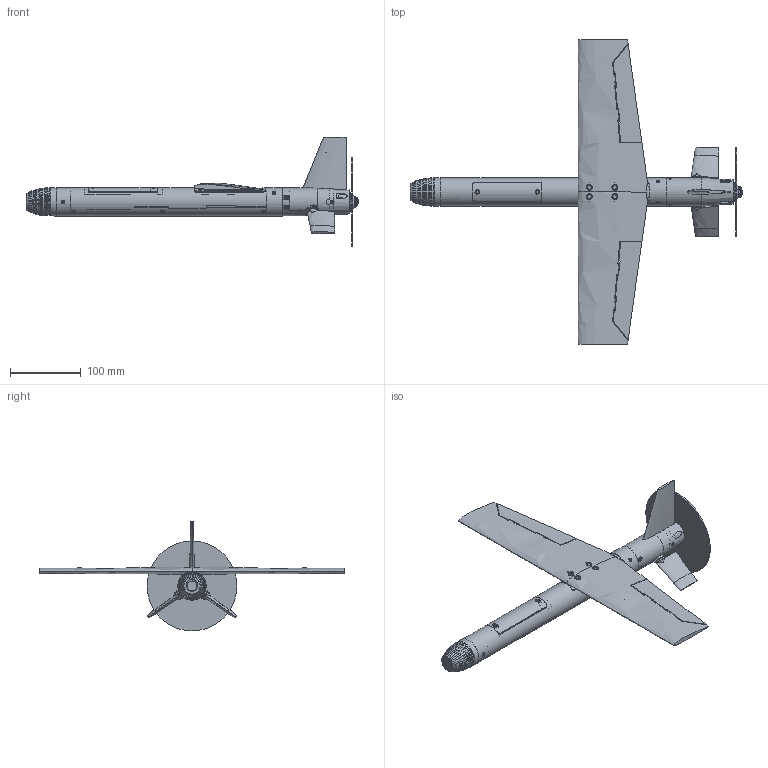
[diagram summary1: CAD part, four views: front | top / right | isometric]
STEP (ISO 10303-21) file: header records copied from the file, then geometry measured from it (millimetres).
FILE_DESCRIPTION(('SkyG Speed 90B - revision C6B-18 - 2026-10-15','C6B-assembly'),'2;1');
FILE_NAME('C6B-assembly_C6B-18','2026-10-15T11:37:26',('Author'),( 'Open CASCADE'),'Open CASCADE STEP processor 7.9','Open CASCADE 7.9' ,'Unknown');
FILE_SCHEMA(('AUTOMOTIVE_DESIGN { 1 0 10303 214 1 1 1 1 }'));
Length unit declared in the file: millimetre
Products named in the file (172): C4; N0M-nose-micro-camera; N0M-vtx-shelf; F3-tail-module; WR-wing-right; WL-wing-left; AR-aileron-right; AL-aileron-left; SR-stabilator-right; SL-stabilator-left; FN-fin; AHR-aileron-horn-right; AHL-aileron-horn-left; THR-tail-horn-right; THL-tail-horn-left; TR-equipment-tray; BF-battery-front-stop; TC-tail-coupler; CW-countersunk-washer; NB1-wing-nut-bar-front; NB2-wing-nut-bar-rear; HL1-hatch-lip-front; HL2-hatch-lip-rear; HF-front-hatch; WF-wing-window-filler; HG-gps-carrier; M1-motor-plate; SP-spinner; ENV-scr_mplate_R; ENV-cw_15; ENV-scr_mplate_L; ENV-cw_16; ENV-motor; ENV-prop_disc; ENV-prop_hub_nut; ENV-battery; ENV-camera_micro19; ENV-cam_screws; ENV-O_o4_camera; ENV-O_window ...
Assembly tree (171 placements, depth 2):
  C4
    N0M-nose-micro-camera
    N0M-vtx-shelf
    F3-tail-module
    WR-wing-right
    WL-wing-left
    AR-aileron-right
    AL-aileron-left
    SR-stabilator-right
    SL-stabilator-left
    FN-fin
    AHR-aileron-horn-right
    AHL-aileron-horn-left
    THR-tail-horn-right
    THL-tail-horn-left
    TR-equipment-tray
    BF-battery-front-stop
    TC-tail-coupler
    CW-countersunk-washer
    NB1-wing-nut-bar-front
    NB2-wing-nut-bar-rear
    HL1-hatch-lip-front
    HL2-hatch-lip-rear
    HF-front-hatch
    WF-wing-window-filler
    HG-gps-carrier
    M1-motor-plate
    SP-spinner
    ENV-scr_mplate_R
    ENV-cw_15
    ENV-scr_mplate_L
    ENV-cw_16
    ENV-motor
    ENV-prop_disc
    ENV-prop_hub_nut
    ENV-battery
    ENV-camera_micro19
    ENV-cam_screws
    ENV-O_o4_camera
    ENV-O_window
    ENV-O_o4_screws
    ENV-O_o4_module
    ENV-vtx
    ENV-gnss
    ENV-flight_controller
    ENV-ail_servo_arm
    ENV-ail_rod_R
    ENV-ail_link_R
    ENV-ail_rod_L
    ENV-ail_link_L
    ENV-ail_spine_R
    ENV-ail_spine_L
    ENV-receiver
    ENV-ant_elrs
    ENV-ant_vtx
    ENV-O_ant_video
    ENV-aileron_servo
    ENV-tail_servo_L
    ENV-tail_servo_R
    ENV-esc
Bounding box: 469.18 x 430 x 155.1 mm (x, y, z)
Volume: 496095.7 mm3; surface area: 354199.1 mm2
Topology: 221 solids, 223 shells, 2850 faces, 7158 edges, 4748 vertices
Faces by surface type: plane 1799, cylinder 612, bspline 237, cone 155, sphere 21, torus 15, revolution 11
Full cylindrical faces by diameter (mm): 0.98 x6, 1.107 x11, 1.2 x22, 1.25 x8, 1.5 x2, 1.6 x20, 1.65 x2, 1.75 x4, 1.9 x1, 2 x34, 2.1 x4, 2.2 x22, 2.5 x2, 2.6 x4, 2.842 x6, 3 x19, 3.05 x2, 3.2 x8, 3.3 x6, 3.8 x2, 3.9 x3, 3.94 x3, 4 x4, 4.9 x16, 5 x14, 5.2 x3, 5.5 x4, 5.6 x3, 6 x5, 6.3 x2
Entity records: 482649 total; most frequent: CARTESIAN_POINT 344876, DIRECTION 21708, ORIENTED_EDGE 14274, PCURVE 14274, DEFINITIONAL_REPRESENTATION 14274, LINE 10001, VECTOR 10001, EDGE_CURVE 7137
